# Generated deterministically by seda-macro-lef-normalizer-v1; recipe orfs-asap7-fakeram-m4-v1.
VERSION 5.8 ;
BUSBITCHARS "[]" ;
DIVIDERCHAR "/" ;

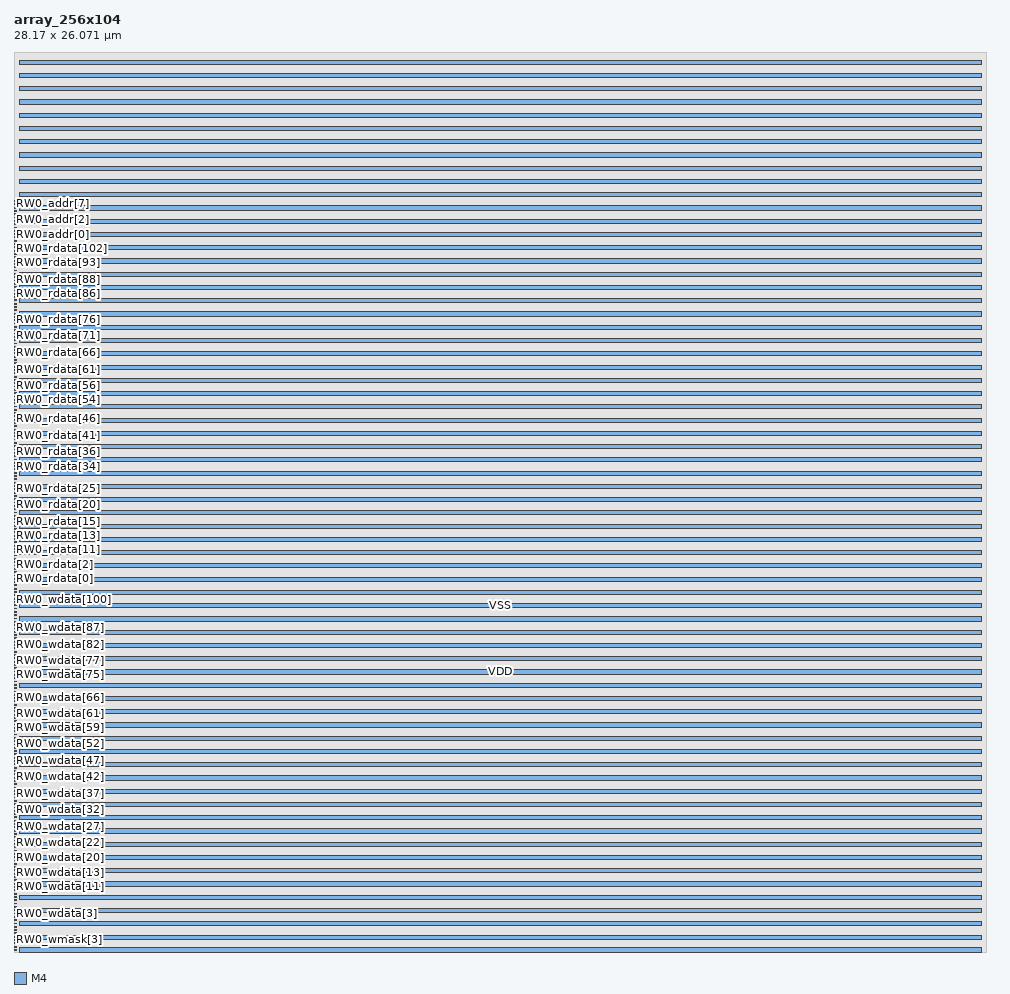
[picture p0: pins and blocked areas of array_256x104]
MACRO array_256x104
  FOREIGN array_256x104 0 0 ;
  CLASS BLOCK ;
  ORIGIN 0 0 ;
  SIZE 28.17 BY 26.071 ;
  SYMMETRY X Y R90 ;
  PIN RW0_wmask[0]
    DIRECTION INPUT ;
    USE SIGNAL ;
    SHAPE ABUTMENT ;
    PORT
      LAYER M4 ;
      RECT 0.000 0.048 0.084 0.072 ;
    END
  END RW0_wmask[0]
  PIN RW0_wmask[1]
    DIRECTION INPUT ;
    USE SIGNAL ;
    SHAPE ABUTMENT ;
    PORT
      LAYER M4 ;
      RECT 0.000 0.144 0.084 0.168 ;
    END
  END RW0_wmask[1]
  PIN RW0_wmask[2]
    DIRECTION INPUT ;
    USE SIGNAL ;
    SHAPE ABUTMENT ;
    PORT
      LAYER M4 ;
      RECT 0.000 0.240 0.084 0.264 ;
    END
  END RW0_wmask[2]
  PIN RW0_wmask[3]
    DIRECTION INPUT ;
    USE SIGNAL ;
    SHAPE ABUTMENT ;
    PORT
      LAYER M4 ;
      RECT 0.000 0.336 0.084 0.360 ;
    END
  END RW0_wmask[3]
  PIN RW0_wmask[4]
    DIRECTION INPUT ;
    USE SIGNAL ;
    SHAPE ABUTMENT ;
    PORT
      LAYER M4 ;
      RECT 0.000 0.432 0.084 0.456 ;
    END
  END RW0_wmask[4]
  PIN RW0_wmask[5]
    DIRECTION INPUT ;
    USE SIGNAL ;
    SHAPE ABUTMENT ;
    PORT
      LAYER M4 ;
      RECT 0.000 0.528 0.084 0.552 ;
    END
  END RW0_wmask[5]
  PIN RW0_wmask[6]
    DIRECTION INPUT ;
    USE SIGNAL ;
    SHAPE ABUTMENT ;
    PORT
      LAYER M4 ;
      RECT 0.000 0.624 0.084 0.648 ;
    END
  END RW0_wmask[6]
  PIN RW0_wmask[7]
    DIRECTION INPUT ;
    USE SIGNAL ;
    SHAPE ABUTMENT ;
    PORT
      LAYER M4 ;
      RECT 0.000 0.720 0.084 0.744 ;
    END
  END RW0_wmask[7]
  PIN RW0_wdata[0]
    DIRECTION INPUT ;
    USE SIGNAL ;
    SHAPE ABUTMENT ;
    PORT
      LAYER M4 ;
      RECT 0.000 0.816 0.084 0.840 ;
    END
  END RW0_wdata[0]
  PIN RW0_wdata[1]
    DIRECTION INPUT ;
    USE SIGNAL ;
    SHAPE ABUTMENT ;
    PORT
      LAYER M4 ;
      RECT 0.000 0.912 0.084 0.936 ;
    END
  END RW0_wdata[1]
  PIN RW0_wdata[2]
    DIRECTION INPUT ;
    USE SIGNAL ;
    SHAPE ABUTMENT ;
    PORT
      LAYER M4 ;
      RECT 0.000 1.008 0.084 1.032 ;
    END
  END RW0_wdata[2]
  PIN RW0_wdata[3]
    DIRECTION INPUT ;
    USE SIGNAL ;
    SHAPE ABUTMENT ;
    PORT
      LAYER M4 ;
      RECT 0.000 1.104 0.084 1.128 ;
    END
  END RW0_wdata[3]
  PIN RW0_wdata[4]
    DIRECTION INPUT ;
    USE SIGNAL ;
    SHAPE ABUTMENT ;
    PORT
      LAYER M4 ;
      RECT 0.000 1.200 0.084 1.224 ;
    END
  END RW0_wdata[4]
  PIN RW0_wdata[5]
    DIRECTION INPUT ;
    USE SIGNAL ;
    SHAPE ABUTMENT ;
    PORT
      LAYER M4 ;
      RECT 0.000 1.296 0.084 1.320 ;
    END
  END RW0_wdata[5]
  PIN RW0_wdata[6]
    DIRECTION INPUT ;
    USE SIGNAL ;
    SHAPE ABUTMENT ;
    PORT
      LAYER M4 ;
      RECT 0.000 1.392 0.084 1.416 ;
    END
  END RW0_wdata[6]
  PIN RW0_wdata[7]
    DIRECTION INPUT ;
    USE SIGNAL ;
    SHAPE ABUTMENT ;
    PORT
      LAYER M4 ;
      RECT 0.000 1.488 0.084 1.512 ;
    END
  END RW0_wdata[7]
  PIN RW0_wdata[8]
    DIRECTION INPUT ;
    USE SIGNAL ;
    SHAPE ABUTMENT ;
    PORT
      LAYER M4 ;
      RECT 0.000 1.584 0.084 1.608 ;
    END
  END RW0_wdata[8]
  PIN RW0_wdata[9]
    DIRECTION INPUT ;
    USE SIGNAL ;
    SHAPE ABUTMENT ;
    PORT
      LAYER M4 ;
      RECT 0.000 1.680 0.084 1.704 ;
    END
  END RW0_wdata[9]
  PIN RW0_wdata[10]
    DIRECTION INPUT ;
    USE SIGNAL ;
    SHAPE ABUTMENT ;
    PORT
      LAYER M4 ;
      RECT 0.000 1.776 0.084 1.800 ;
    END
  END RW0_wdata[10]
  PIN RW0_wdata[11]
    DIRECTION INPUT ;
    USE SIGNAL ;
    SHAPE ABUTMENT ;
    PORT
      LAYER M4 ;
      RECT 0.000 1.872 0.084 1.896 ;
    END
  END RW0_wdata[11]
  PIN RW0_wdata[12]
    DIRECTION INPUT ;
    USE SIGNAL ;
    SHAPE ABUTMENT ;
    PORT
      LAYER M4 ;
      RECT 0.000 1.968 0.084 1.992 ;
    END
  END RW0_wdata[12]
  PIN RW0_wdata[13]
    DIRECTION INPUT ;
    USE SIGNAL ;
    SHAPE ABUTMENT ;
    PORT
      LAYER M4 ;
      RECT 0.000 2.064 0.084 2.088 ;
    END
  END RW0_wdata[13]
  PIN RW0_wdata[14]
    DIRECTION INPUT ;
    USE SIGNAL ;
    SHAPE ABUTMENT ;
    PORT
      LAYER M4 ;
      RECT 0.000 2.160 0.084 2.184 ;
    END
  END RW0_wdata[14]
  PIN RW0_wdata[15]
    DIRECTION INPUT ;
    USE SIGNAL ;
    SHAPE ABUTMENT ;
    PORT
      LAYER M4 ;
      RECT 0.000 2.256 0.084 2.280 ;
    END
  END RW0_wdata[15]
  PIN RW0_wdata[16]
    DIRECTION INPUT ;
    USE SIGNAL ;
    SHAPE ABUTMENT ;
    PORT
      LAYER M4 ;
      RECT 0.000 2.352 0.084 2.376 ;
    END
  END RW0_wdata[16]
  PIN RW0_wdata[17]
    DIRECTION INPUT ;
    USE SIGNAL ;
    SHAPE ABUTMENT ;
    PORT
      LAYER M4 ;
      RECT 0.000 2.448 0.084 2.472 ;
    END
  END RW0_wdata[17]
  PIN RW0_wdata[18]
    DIRECTION INPUT ;
    USE SIGNAL ;
    SHAPE ABUTMENT ;
    PORT
      LAYER M4 ;
      RECT 0.000 2.544 0.084 2.568 ;
    END
  END RW0_wdata[18]
  PIN RW0_wdata[19]
    DIRECTION INPUT ;
    USE SIGNAL ;
    SHAPE ABUTMENT ;
    PORT
      LAYER M4 ;
      RECT 0.000 2.640 0.084 2.664 ;
    END
  END RW0_wdata[19]
  PIN RW0_wdata[20]
    DIRECTION INPUT ;
    USE SIGNAL ;
    SHAPE ABUTMENT ;
    PORT
      LAYER M4 ;
      RECT 0.000 2.736 0.084 2.760 ;
    END
  END RW0_wdata[20]
  PIN RW0_wdata[21]
    DIRECTION INPUT ;
    USE SIGNAL ;
    SHAPE ABUTMENT ;
    PORT
      LAYER M4 ;
      RECT 0.000 2.832 0.084 2.856 ;
    END
  END RW0_wdata[21]
  PIN RW0_wdata[22]
    DIRECTION INPUT ;
    USE SIGNAL ;
    SHAPE ABUTMENT ;
    PORT
      LAYER M4 ;
      RECT 0.000 2.928 0.084 2.952 ;
    END
  END RW0_wdata[22]
  PIN RW0_wdata[23]
    DIRECTION INPUT ;
    USE SIGNAL ;
    SHAPE ABUTMENT ;
    PORT
      LAYER M4 ;
      RECT 0.000 3.024 0.084 3.048 ;
    END
  END RW0_wdata[23]
  PIN RW0_wdata[24]
    DIRECTION INPUT ;
    USE SIGNAL ;
    SHAPE ABUTMENT ;
    PORT
      LAYER M4 ;
      RECT 0.000 3.120 0.084 3.144 ;
    END
  END RW0_wdata[24]
  PIN RW0_wdata[25]
    DIRECTION INPUT ;
    USE SIGNAL ;
    SHAPE ABUTMENT ;
    PORT
      LAYER M4 ;
      RECT 0.000 3.216 0.084 3.240 ;
    END
  END RW0_wdata[25]
  PIN RW0_wdata[26]
    DIRECTION INPUT ;
    USE SIGNAL ;
    SHAPE ABUTMENT ;
    PORT
      LAYER M4 ;
      RECT 0.000 3.312 0.084 3.336 ;
    END
  END RW0_wdata[26]
  PIN RW0_wdata[27]
    DIRECTION INPUT ;
    USE SIGNAL ;
    SHAPE ABUTMENT ;
    PORT
      LAYER M4 ;
      RECT 0.000 3.408 0.084 3.432 ;
    END
  END RW0_wdata[27]
  PIN RW0_wdata[28]
    DIRECTION INPUT ;
    USE SIGNAL ;
    SHAPE ABUTMENT ;
    PORT
      LAYER M4 ;
      RECT 0.000 3.504 0.084 3.528 ;
    END
  END RW0_wdata[28]
  PIN RW0_wdata[29]
    DIRECTION INPUT ;
    USE SIGNAL ;
    SHAPE ABUTMENT ;
    PORT
      LAYER M4 ;
      RECT 0.000 3.600 0.084 3.624 ;
    END
  END RW0_wdata[29]
  PIN RW0_wdata[30]
    DIRECTION INPUT ;
    USE SIGNAL ;
    SHAPE ABUTMENT ;
    PORT
      LAYER M4 ;
      RECT 0.000 3.696 0.084 3.720 ;
    END
  END RW0_wdata[30]
  PIN RW0_wdata[31]
    DIRECTION INPUT ;
    USE SIGNAL ;
    SHAPE ABUTMENT ;
    PORT
      LAYER M4 ;
      RECT 0.000 3.792 0.084 3.816 ;
    END
  END RW0_wdata[31]
  PIN RW0_wdata[32]
    DIRECTION INPUT ;
    USE SIGNAL ;
    SHAPE ABUTMENT ;
    PORT
      LAYER M4 ;
      RECT 0.000 3.888 0.084 3.912 ;
    END
  END RW0_wdata[32]
  PIN RW0_wdata[33]
    DIRECTION INPUT ;
    USE SIGNAL ;
    SHAPE ABUTMENT ;
    PORT
      LAYER M4 ;
      RECT 0.000 3.984 0.084 4.008 ;
    END
  END RW0_wdata[33]
  PIN RW0_wdata[34]
    DIRECTION INPUT ;
    USE SIGNAL ;
    SHAPE ABUTMENT ;
    PORT
      LAYER M4 ;
      RECT 0.000 4.080 0.084 4.104 ;
    END
  END RW0_wdata[34]
  PIN RW0_wdata[35]
    DIRECTION INPUT ;
    USE SIGNAL ;
    SHAPE ABUTMENT ;
    PORT
      LAYER M4 ;
      RECT 0.000 4.176 0.084 4.200 ;
    END
  END RW0_wdata[35]
  PIN RW0_wdata[36]
    DIRECTION INPUT ;
    USE SIGNAL ;
    SHAPE ABUTMENT ;
    PORT
      LAYER M4 ;
      RECT 0.000 4.272 0.084 4.296 ;
    END
  END RW0_wdata[36]
  PIN RW0_wdata[37]
    DIRECTION INPUT ;
    USE SIGNAL ;
    SHAPE ABUTMENT ;
    PORT
      LAYER M4 ;
      RECT 0.000 4.368 0.084 4.392 ;
    END
  END RW0_wdata[37]
  PIN RW0_wdata[38]
    DIRECTION INPUT ;
    USE SIGNAL ;
    SHAPE ABUTMENT ;
    PORT
      LAYER M4 ;
      RECT 0.000 4.464 0.084 4.488 ;
    END
  END RW0_wdata[38]
  PIN RW0_wdata[39]
    DIRECTION INPUT ;
    USE SIGNAL ;
    SHAPE ABUTMENT ;
    PORT
      LAYER M4 ;
      RECT 0.000 4.560 0.084 4.584 ;
    END
  END RW0_wdata[39]
  PIN RW0_wdata[40]
    DIRECTION INPUT ;
    USE SIGNAL ;
    SHAPE ABUTMENT ;
    PORT
      LAYER M4 ;
      RECT 0.000 4.656 0.084 4.680 ;
    END
  END RW0_wdata[40]
  PIN RW0_wdata[41]
    DIRECTION INPUT ;
    USE SIGNAL ;
    SHAPE ABUTMENT ;
    PORT
      LAYER M4 ;
      RECT 0.000 4.752 0.084 4.776 ;
    END
  END RW0_wdata[41]
  PIN RW0_wdata[42]
    DIRECTION INPUT ;
    USE SIGNAL ;
    SHAPE ABUTMENT ;
    PORT
      LAYER M4 ;
      RECT 0.000 4.848 0.084 4.872 ;
    END
  END RW0_wdata[42]
  PIN RW0_wdata[43]
    DIRECTION INPUT ;
    USE SIGNAL ;
    SHAPE ABUTMENT ;
    PORT
      LAYER M4 ;
      RECT 0.000 4.944 0.084 4.968 ;
    END
  END RW0_wdata[43]
  PIN RW0_wdata[44]
    DIRECTION INPUT ;
    USE SIGNAL ;
    SHAPE ABUTMENT ;
    PORT
      LAYER M4 ;
      RECT 0.000 5.040 0.084 5.064 ;
    END
  END RW0_wdata[44]
  PIN RW0_wdata[45]
    DIRECTION INPUT ;
    USE SIGNAL ;
    SHAPE ABUTMENT ;
    PORT
      LAYER M4 ;
      RECT 0.000 5.136 0.084 5.160 ;
    END
  END RW0_wdata[45]
  PIN RW0_wdata[46]
    DIRECTION INPUT ;
    USE SIGNAL ;
    SHAPE ABUTMENT ;
    PORT
      LAYER M4 ;
      RECT 0.000 5.232 0.084 5.256 ;
    END
  END RW0_wdata[46]
  PIN RW0_wdata[47]
    DIRECTION INPUT ;
    USE SIGNAL ;
    SHAPE ABUTMENT ;
    PORT
      LAYER M4 ;
      RECT 0.000 5.328 0.084 5.352 ;
    END
  END RW0_wdata[47]
  PIN RW0_wdata[48]
    DIRECTION INPUT ;
    USE SIGNAL ;
    SHAPE ABUTMENT ;
    PORT
      LAYER M4 ;
      RECT 0.000 5.424 0.084 5.448 ;
    END
  END RW0_wdata[48]
  PIN RW0_wdata[49]
    DIRECTION INPUT ;
    USE SIGNAL ;
    SHAPE ABUTMENT ;
    PORT
      LAYER M4 ;
      RECT 0.000 5.520 0.084 5.544 ;
    END
  END RW0_wdata[49]
  PIN RW0_wdata[50]
    DIRECTION INPUT ;
    USE SIGNAL ;
    SHAPE ABUTMENT ;
    PORT
      LAYER M4 ;
      RECT 0.000 5.616 0.084 5.640 ;
    END
  END RW0_wdata[50]
  PIN RW0_wdata[51]
    DIRECTION INPUT ;
    USE SIGNAL ;
    SHAPE ABUTMENT ;
    PORT
      LAYER M4 ;
      RECT 0.000 5.712 0.084 5.736 ;
    END
  END RW0_wdata[51]
  PIN RW0_wdata[52]
    DIRECTION INPUT ;
    USE SIGNAL ;
    SHAPE ABUTMENT ;
    PORT
      LAYER M4 ;
      RECT 0.000 5.808 0.084 5.832 ;
    END
  END RW0_wdata[52]
  PIN RW0_wdata[53]
    DIRECTION INPUT ;
    USE SIGNAL ;
    SHAPE ABUTMENT ;
    PORT
      LAYER M4 ;
      RECT 0.000 5.904 0.084 5.928 ;
    END
  END RW0_wdata[53]
  PIN RW0_wdata[54]
    DIRECTION INPUT ;
    USE SIGNAL ;
    SHAPE ABUTMENT ;
    PORT
      LAYER M4 ;
      RECT 0.000 6.000 0.084 6.024 ;
    END
  END RW0_wdata[54]
  PIN RW0_wdata[55]
    DIRECTION INPUT ;
    USE SIGNAL ;
    SHAPE ABUTMENT ;
    PORT
      LAYER M4 ;
      RECT 0.000 6.096 0.084 6.120 ;
    END
  END RW0_wdata[55]
  PIN RW0_wdata[56]
    DIRECTION INPUT ;
    USE SIGNAL ;
    SHAPE ABUTMENT ;
    PORT
      LAYER M4 ;
      RECT 0.000 6.192 0.084 6.216 ;
    END
  END RW0_wdata[56]
  PIN RW0_wdata[57]
    DIRECTION INPUT ;
    USE SIGNAL ;
    SHAPE ABUTMENT ;
    PORT
      LAYER M4 ;
      RECT 0.000 6.288 0.084 6.312 ;
    END
  END RW0_wdata[57]
  PIN RW0_wdata[58]
    DIRECTION INPUT ;
    USE SIGNAL ;
    SHAPE ABUTMENT ;
    PORT
      LAYER M4 ;
      RECT 0.000 6.384 0.084 6.408 ;
    END
  END RW0_wdata[58]
  PIN RW0_wdata[59]
    DIRECTION INPUT ;
    USE SIGNAL ;
    SHAPE ABUTMENT ;
    PORT
      LAYER M4 ;
      RECT 0.000 6.480 0.084 6.504 ;
    END
  END RW0_wdata[59]
  PIN RW0_wdata[60]
    DIRECTION INPUT ;
    USE SIGNAL ;
    SHAPE ABUTMENT ;
    PORT
      LAYER M4 ;
      RECT 0.000 6.576 0.084 6.600 ;
    END
  END RW0_wdata[60]
  PIN RW0_wdata[61]
    DIRECTION INPUT ;
    USE SIGNAL ;
    SHAPE ABUTMENT ;
    PORT
      LAYER M4 ;
      RECT 0.000 6.672 0.084 6.696 ;
    END
  END RW0_wdata[61]
  PIN RW0_wdata[62]
    DIRECTION INPUT ;
    USE SIGNAL ;
    SHAPE ABUTMENT ;
    PORT
      LAYER M4 ;
      RECT 0.000 6.768 0.084 6.792 ;
    END
  END RW0_wdata[62]
  PIN RW0_wdata[63]
    DIRECTION INPUT ;
    USE SIGNAL ;
    SHAPE ABUTMENT ;
    PORT
      LAYER M4 ;
      RECT 0.000 6.864 0.084 6.888 ;
    END
  END RW0_wdata[63]
  PIN RW0_wdata[64]
    DIRECTION INPUT ;
    USE SIGNAL ;
    SHAPE ABUTMENT ;
    PORT
      LAYER M4 ;
      RECT 0.000 6.960 0.084 6.984 ;
    END
  END RW0_wdata[64]
  PIN RW0_wdata[65]
    DIRECTION INPUT ;
    USE SIGNAL ;
    SHAPE ABUTMENT ;
    PORT
      LAYER M4 ;
      RECT 0.000 7.056 0.084 7.080 ;
    END
  END RW0_wdata[65]
  PIN RW0_wdata[66]
    DIRECTION INPUT ;
    USE SIGNAL ;
    SHAPE ABUTMENT ;
    PORT
      LAYER M4 ;
      RECT 0.000 7.152 0.084 7.176 ;
    END
  END RW0_wdata[66]
  PIN RW0_wdata[67]
    DIRECTION INPUT ;
    USE SIGNAL ;
    SHAPE ABUTMENT ;
    PORT
      LAYER M4 ;
      RECT 0.000 7.248 0.084 7.272 ;
    END
  END RW0_wdata[67]
  PIN RW0_wdata[68]
    DIRECTION INPUT ;
    USE SIGNAL ;
    SHAPE ABUTMENT ;
    PORT
      LAYER M4 ;
      RECT 0.000 7.344 0.084 7.368 ;
    END
  END RW0_wdata[68]
  PIN RW0_wdata[69]
    DIRECTION INPUT ;
    USE SIGNAL ;
    SHAPE ABUTMENT ;
    PORT
      LAYER M4 ;
      RECT 0.000 7.440 0.084 7.464 ;
    END
  END RW0_wdata[69]
  PIN RW0_wdata[70]
    DIRECTION INPUT ;
    USE SIGNAL ;
    SHAPE ABUTMENT ;
    PORT
      LAYER M4 ;
      RECT 0.000 7.536 0.084 7.560 ;
    END
  END RW0_wdata[70]
  PIN RW0_wdata[71]
    DIRECTION INPUT ;
    USE SIGNAL ;
    SHAPE ABUTMENT ;
    PORT
      LAYER M4 ;
      RECT 0.000 7.632 0.084 7.656 ;
    END
  END RW0_wdata[71]
  PIN RW0_wdata[72]
    DIRECTION INPUT ;
    USE SIGNAL ;
    SHAPE ABUTMENT ;
    PORT
      LAYER M4 ;
      RECT 0.000 7.728 0.084 7.752 ;
    END
  END RW0_wdata[72]
  PIN RW0_wdata[73]
    DIRECTION INPUT ;
    USE SIGNAL ;
    SHAPE ABUTMENT ;
    PORT
      LAYER M4 ;
      RECT 0.000 7.824 0.084 7.848 ;
    END
  END RW0_wdata[73]
  PIN RW0_wdata[74]
    DIRECTION INPUT ;
    USE SIGNAL ;
    SHAPE ABUTMENT ;
    PORT
      LAYER M4 ;
      RECT 0.000 7.920 0.084 7.944 ;
    END
  END RW0_wdata[74]
  PIN RW0_wdata[75]
    DIRECTION INPUT ;
    USE SIGNAL ;
    SHAPE ABUTMENT ;
    PORT
      LAYER M4 ;
      RECT 0.000 8.016 0.084 8.040 ;
    END
  END RW0_wdata[75]
  PIN RW0_wdata[76]
    DIRECTION INPUT ;
    USE SIGNAL ;
    SHAPE ABUTMENT ;
    PORT
      LAYER M4 ;
      RECT 0.000 8.112 0.084 8.136 ;
    END
  END RW0_wdata[76]
  PIN RW0_wdata[77]
    DIRECTION INPUT ;
    USE SIGNAL ;
    SHAPE ABUTMENT ;
    PORT
      LAYER M4 ;
      RECT 0.000 8.208 0.084 8.232 ;
    END
  END RW0_wdata[77]
  PIN RW0_wdata[78]
    DIRECTION INPUT ;
    USE SIGNAL ;
    SHAPE ABUTMENT ;
    PORT
      LAYER M4 ;
      RECT 0.000 8.304 0.084 8.328 ;
    END
  END RW0_wdata[78]
  PIN RW0_wdata[79]
    DIRECTION INPUT ;
    USE SIGNAL ;
    SHAPE ABUTMENT ;
    PORT
      LAYER M4 ;
      RECT 0.000 8.400 0.084 8.424 ;
    END
  END RW0_wdata[79]
  PIN RW0_wdata[80]
    DIRECTION INPUT ;
    USE SIGNAL ;
    SHAPE ABUTMENT ;
    PORT
      LAYER M4 ;
      RECT 0.000 8.496 0.084 8.520 ;
    END
  END RW0_wdata[80]
  PIN RW0_wdata[81]
    DIRECTION INPUT ;
    USE SIGNAL ;
    SHAPE ABUTMENT ;
    PORT
      LAYER M4 ;
      RECT 0.000 8.592 0.084 8.616 ;
    END
  END RW0_wdata[81]
  PIN RW0_wdata[82]
    DIRECTION INPUT ;
    USE SIGNAL ;
    SHAPE ABUTMENT ;
    PORT
      LAYER M4 ;
      RECT 0.000 8.688 0.084 8.712 ;
    END
  END RW0_wdata[82]
  PIN RW0_wdata[83]
    DIRECTION INPUT ;
    USE SIGNAL ;
    SHAPE ABUTMENT ;
    PORT
      LAYER M4 ;
      RECT 0.000 8.784 0.084 8.808 ;
    END
  END RW0_wdata[83]
  PIN RW0_wdata[84]
    DIRECTION INPUT ;
    USE SIGNAL ;
    SHAPE ABUTMENT ;
    PORT
      LAYER M4 ;
      RECT 0.000 8.880 0.084 8.904 ;
    END
  END RW0_wdata[84]
  PIN RW0_wdata[85]
    DIRECTION INPUT ;
    USE SIGNAL ;
    SHAPE ABUTMENT ;
    PORT
      LAYER M4 ;
      RECT 0.000 8.976 0.084 9.000 ;
    END
  END RW0_wdata[85]
  PIN RW0_wdata[86]
    DIRECTION INPUT ;
    USE SIGNAL ;
    SHAPE ABUTMENT ;
    PORT
      LAYER M4 ;
      RECT 0.000 9.072 0.084 9.096 ;
    END
  END RW0_wdata[86]
  PIN RW0_wdata[87]
    DIRECTION INPUT ;
    USE SIGNAL ;
    SHAPE ABUTMENT ;
    PORT
      LAYER M4 ;
      RECT 0.000 9.168 0.084 9.192 ;
    END
  END RW0_wdata[87]
  PIN RW0_wdata[88]
    DIRECTION INPUT ;
    USE SIGNAL ;
    SHAPE ABUTMENT ;
    PORT
      LAYER M4 ;
      RECT 0.000 9.264 0.084 9.288 ;
    END
  END RW0_wdata[88]
  PIN RW0_wdata[89]
    DIRECTION INPUT ;
    USE SIGNAL ;
    SHAPE ABUTMENT ;
    PORT
      LAYER M4 ;
      RECT 0.000 9.360 0.084 9.384 ;
    END
  END RW0_wdata[89]
  PIN RW0_wdata[90]
    DIRECTION INPUT ;
    USE SIGNAL ;
    SHAPE ABUTMENT ;
    PORT
      LAYER M4 ;
      RECT 0.000 9.456 0.084 9.480 ;
    END
  END RW0_wdata[90]
  PIN RW0_wdata[91]
    DIRECTION INPUT ;
    USE SIGNAL ;
    SHAPE ABUTMENT ;
    PORT
      LAYER M4 ;
      RECT 0.000 9.552 0.084 9.576 ;
    END
  END RW0_wdata[91]
  PIN RW0_wdata[92]
    DIRECTION INPUT ;
    USE SIGNAL ;
    SHAPE ABUTMENT ;
    PORT
      LAYER M4 ;
      RECT 0.000 9.648 0.084 9.672 ;
    END
  END RW0_wdata[92]
  PIN RW0_wdata[93]
    DIRECTION INPUT ;
    USE SIGNAL ;
    SHAPE ABUTMENT ;
    PORT
      LAYER M4 ;
      RECT 0.000 9.744 0.084 9.768 ;
    END
  END RW0_wdata[93]
  PIN RW0_wdata[94]
    DIRECTION INPUT ;
    USE SIGNAL ;
    SHAPE ABUTMENT ;
    PORT
      LAYER M4 ;
      RECT 0.000 9.840 0.084 9.864 ;
    END
  END RW0_wdata[94]
  PIN RW0_wdata[95]
    DIRECTION INPUT ;
    USE SIGNAL ;
    SHAPE ABUTMENT ;
    PORT
      LAYER M4 ;
      RECT 0.000 9.936 0.084 9.960 ;
    END
  END RW0_wdata[95]
  PIN RW0_wdata[96]
    DIRECTION INPUT ;
    USE SIGNAL ;
    SHAPE ABUTMENT ;
    PORT
      LAYER M4 ;
      RECT 0.000 10.032 0.084 10.056 ;
    END
  END RW0_wdata[96]
  PIN RW0_wdata[97]
    DIRECTION INPUT ;
    USE SIGNAL ;
    SHAPE ABUTMENT ;
    PORT
      LAYER M4 ;
      RECT 0.000 10.128 0.084 10.152 ;
    END
  END RW0_wdata[97]
  PIN RW0_wdata[98]
    DIRECTION INPUT ;
    USE SIGNAL ;
    SHAPE ABUTMENT ;
    PORT
      LAYER M4 ;
      RECT 0.000 10.224 0.084 10.248 ;
    END
  END RW0_wdata[98]
  PIN RW0_wdata[99]
    DIRECTION INPUT ;
    USE SIGNAL ;
    SHAPE ABUTMENT ;
    PORT
      LAYER M4 ;
      RECT 0.000 10.320 0.084 10.344 ;
    END
  END RW0_wdata[99]
  PIN RW0_wdata[100]
    DIRECTION INPUT ;
    USE SIGNAL ;
    SHAPE ABUTMENT ;
    PORT
      LAYER M4 ;
      RECT 0.000 10.416 0.084 10.440 ;
    END
  END RW0_wdata[100]
  PIN RW0_wdata[101]
    DIRECTION INPUT ;
    USE SIGNAL ;
    SHAPE ABUTMENT ;
    PORT
      LAYER M4 ;
      RECT 0.000 10.512 0.084 10.536 ;
    END
  END RW0_wdata[101]
  PIN RW0_wdata[102]
    DIRECTION INPUT ;
    USE SIGNAL ;
    SHAPE ABUTMENT ;
    PORT
      LAYER M4 ;
      RECT 0.000 10.608 0.084 10.632 ;
    END
  END RW0_wdata[102]
  PIN RW0_wdata[103]
    DIRECTION INPUT ;
    USE SIGNAL ;
    SHAPE ABUTMENT ;
    PORT
      LAYER M4 ;
      RECT 0.000 10.704 0.084 10.728 ;
    END
  END RW0_wdata[103]
  PIN RW0_rdata[0]
    DIRECTION OUTPUT ;
    USE SIGNAL ;
    SHAPE ABUTMENT ;
    PORT
      LAYER M4 ;
      RECT 0.000 10.800 0.084 10.824 ;
    END
  END RW0_rdata[0]
  PIN RW0_rdata[1]
    DIRECTION OUTPUT ;
    USE SIGNAL ;
    SHAPE ABUTMENT ;
    PORT
      LAYER M4 ;
      RECT 0.000 10.896 0.084 10.920 ;
    END
  END RW0_rdata[1]
  PIN RW0_rdata[2]
    DIRECTION OUTPUT ;
    USE SIGNAL ;
    SHAPE ABUTMENT ;
    PORT
      LAYER M4 ;
      RECT 0.000 10.992 0.084 11.016 ;
    END
  END RW0_rdata[2]
  PIN RW0_rdata[3]
    DIRECTION OUTPUT ;
    USE SIGNAL ;
    SHAPE ABUTMENT ;
    PORT
      LAYER M4 ;
      RECT 0.000 11.088 0.084 11.112 ;
    END
  END RW0_rdata[3]
  PIN RW0_rdata[4]
    DIRECTION OUTPUT ;
    USE SIGNAL ;
    SHAPE ABUTMENT ;
    PORT
      LAYER M4 ;
      RECT 0.000 11.184 0.084 11.208 ;
    END
  END RW0_rdata[4]
  PIN RW0_rdata[5]
    DIRECTION OUTPUT ;
    USE SIGNAL ;
    SHAPE ABUTMENT ;
    PORT
      LAYER M4 ;
      RECT 0.000 11.280 0.084 11.304 ;
    END
  END RW0_rdata[5]
  PIN RW0_rdata[6]
    DIRECTION OUTPUT ;
    USE SIGNAL ;
    SHAPE ABUTMENT ;
    PORT
      LAYER M4 ;
      RECT 0.000 11.376 0.084 11.400 ;
    END
  END RW0_rdata[6]
  PIN RW0_rdata[7]
    DIRECTION OUTPUT ;
    USE SIGNAL ;
    SHAPE ABUTMENT ;
    PORT
      LAYER M4 ;
      RECT 0.000 11.472 0.084 11.496 ;
    END
  END RW0_rdata[7]
  PIN RW0_rdata[8]
    DIRECTION OUTPUT ;
    USE SIGNAL ;
    SHAPE ABUTMENT ;
    PORT
      LAYER M4 ;
      RECT 0.000 11.568 0.084 11.592 ;
    END
  END RW0_rdata[8]
  PIN RW0_rdata[9]
    DIRECTION OUTPUT ;
    USE SIGNAL ;
    SHAPE ABUTMENT ;
    PORT
      LAYER M4 ;
      RECT 0.000 11.664 0.084 11.688 ;
    END
  END RW0_rdata[9]
  PIN RW0_rdata[10]
    DIRECTION OUTPUT ;
    USE SIGNAL ;
    SHAPE ABUTMENT ;
    PORT
      LAYER M4 ;
      RECT 0.000 11.760 0.084 11.784 ;
    END
  END RW0_rdata[10]
  PIN RW0_rdata[11]
    DIRECTION OUTPUT ;
    USE SIGNAL ;
    SHAPE ABUTMENT ;
    PORT
      LAYER M4 ;
      RECT 0.000 11.856 0.084 11.880 ;
    END
  END RW0_rdata[11]
  PIN RW0_rdata[12]
    DIRECTION OUTPUT ;
    USE SIGNAL ;
    SHAPE ABUTMENT ;
    PORT
      LAYER M4 ;
      RECT 0.000 11.952 0.084 11.976 ;
    END
  END RW0_rdata[12]
  PIN RW0_rdata[13]
    DIRECTION OUTPUT ;
    USE SIGNAL ;
    SHAPE ABUTMENT ;
    PORT
      LAYER M4 ;
      RECT 0.000 12.048 0.084 12.072 ;
    END
  END RW0_rdata[13]
  PIN RW0_rdata[14]
    DIRECTION OUTPUT ;
    USE SIGNAL ;
    SHAPE ABUTMENT ;
    PORT
      LAYER M4 ;
      RECT 0.000 12.144 0.084 12.168 ;
    END
  END RW0_rdata[14]
  PIN RW0_rdata[15]
    DIRECTION OUTPUT ;
    USE SIGNAL ;
    SHAPE ABUTMENT ;
    PORT
      LAYER M4 ;
      RECT 0.000 12.240 0.084 12.264 ;
    END
  END RW0_rdata[15]
  PIN RW0_rdata[16]
    DIRECTION OUTPUT ;
    USE SIGNAL ;
    SHAPE ABUTMENT ;
    PORT
      LAYER M4 ;
      RECT 0.000 12.336 0.084 12.360 ;
    END
  END RW0_rdata[16]
  PIN RW0_rdata[17]
    DIRECTION OUTPUT ;
    USE SIGNAL ;
    SHAPE ABUTMENT ;
    PORT
      LAYER M4 ;
      RECT 0.000 12.432 0.084 12.456 ;
    END
  END RW0_rdata[17]
  PIN RW0_rdata[18]
    DIRECTION OUTPUT ;
    USE SIGNAL ;
    SHAPE ABUTMENT ;
    PORT
      LAYER M4 ;
      RECT 0.000 12.528 0.084 12.552 ;
    END
  END RW0_rdata[18]
  PIN RW0_rdata[19]
    DIRECTION OUTPUT ;
    USE SIGNAL ;
    SHAPE ABUTMENT ;
    PORT
      LAYER M4 ;
      RECT 0.000 12.624 0.084 12.648 ;
    END
  END RW0_rdata[19]
  PIN RW0_rdata[20]
    DIRECTION OUTPUT ;
    USE SIGNAL ;
    SHAPE ABUTMENT ;
    PORT
      LAYER M4 ;
      RECT 0.000 12.720 0.084 12.744 ;
    END
  END RW0_rdata[20]
  PIN RW0_rdata[21]
    DIRECTION OUTPUT ;
    USE SIGNAL ;
    SHAPE ABUTMENT ;
    PORT
      LAYER M4 ;
      RECT 0.000 12.816 0.084 12.840 ;
    END
  END RW0_rdata[21]
  PIN RW0_rdata[22]
    DIRECTION OUTPUT ;
    USE SIGNAL ;
    SHAPE ABUTMENT ;
    PORT
      LAYER M4 ;
      RECT 0.000 12.912 0.084 12.936 ;
    END
  END RW0_rdata[22]
  PIN RW0_rdata[23]
    DIRECTION OUTPUT ;
    USE SIGNAL ;
    SHAPE ABUTMENT ;
    PORT
      LAYER M4 ;
      RECT 0.000 13.008 0.084 13.032 ;
    END
  END RW0_rdata[23]
  PIN RW0_rdata[24]
    DIRECTION OUTPUT ;
    USE SIGNAL ;
    SHAPE ABUTMENT ;
    PORT
      LAYER M4 ;
      RECT 0.000 13.104 0.084 13.128 ;
    END
  END RW0_rdata[24]
  PIN RW0_rdata[25]
    DIRECTION OUTPUT ;
    USE SIGNAL ;
    SHAPE ABUTMENT ;
    PORT
      LAYER M4 ;
      RECT 0.000 13.200 0.084 13.224 ;
    END
  END RW0_rdata[25]
  PIN RW0_rdata[26]
    DIRECTION OUTPUT ;
    USE SIGNAL ;
    SHAPE ABUTMENT ;
    PORT
      LAYER M4 ;
      RECT 0.000 13.296 0.084 13.320 ;
    END
  END RW0_rdata[26]
  PIN RW0_rdata[27]
    DIRECTION OUTPUT ;
    USE SIGNAL ;
    SHAPE ABUTMENT ;
    PORT
      LAYER M4 ;
      RECT 0.000 13.392 0.084 13.416 ;
    END
  END RW0_rdata[27]
  PIN RW0_rdata[28]
    DIRECTION OUTPUT ;
    USE SIGNAL ;
    SHAPE ABUTMENT ;
    PORT
      LAYER M4 ;
      RECT 0.000 13.488 0.084 13.512 ;
    END
  END RW0_rdata[28]
  PIN RW0_rdata[29]
    DIRECTION OUTPUT ;
    USE SIGNAL ;
    SHAPE ABUTMENT ;
    PORT
      LAYER M4 ;
      RECT 0.000 13.584 0.084 13.608 ;
    END
  END RW0_rdata[29]
  PIN RW0_rdata[30]
    DIRECTION OUTPUT ;
    USE SIGNAL ;
    SHAPE ABUTMENT ;
    PORT
      LAYER M4 ;
      RECT 0.000 13.680 0.084 13.704 ;
    END
  END RW0_rdata[30]
  PIN RW0_rdata[31]
    DIRECTION OUTPUT ;
    USE SIGNAL ;
    SHAPE ABUTMENT ;
    PORT
      LAYER M4 ;
      RECT 0.000 13.776 0.084 13.800 ;
    END
  END RW0_rdata[31]
  PIN RW0_rdata[32]
    DIRECTION OUTPUT ;
    USE SIGNAL ;
    SHAPE ABUTMENT ;
    PORT
      LAYER M4 ;
      RECT 0.000 13.872 0.084 13.896 ;
    END
  END RW0_rdata[32]
  PIN RW0_rdata[33]
    DIRECTION OUTPUT ;
    USE SIGNAL ;
    SHAPE ABUTMENT ;
    PORT
      LAYER M4 ;
      RECT 0.000 13.968 0.084 13.992 ;
    END
  END RW0_rdata[33]
  PIN RW0_rdata[34]
    DIRECTION OUTPUT ;
    USE SIGNAL ;
    SHAPE ABUTMENT ;
    PORT
      LAYER M4 ;
      RECT 0.000 14.064 0.084 14.088 ;
    END
  END RW0_rdata[34]
  PIN RW0_rdata[35]
    DIRECTION OUTPUT ;
    USE SIGNAL ;
    SHAPE ABUTMENT ;
    PORT
      LAYER M4 ;
      RECT 0.000 14.160 0.084 14.184 ;
    END
  END RW0_rdata[35]
  PIN RW0_rdata[36]
    DIRECTION OUTPUT ;
    USE SIGNAL ;
    SHAPE ABUTMENT ;
    PORT
      LAYER M4 ;
      RECT 0.000 14.256 0.084 14.280 ;
    END
  END RW0_rdata[36]
  PIN RW0_rdata[37]
    DIRECTION OUTPUT ;
    USE SIGNAL ;
    SHAPE ABUTMENT ;
    PORT
      LAYER M4 ;
      RECT 0.000 14.352 0.084 14.376 ;
    END
  END RW0_rdata[37]
  PIN RW0_rdata[38]
    DIRECTION OUTPUT ;
    USE SIGNAL ;
    SHAPE ABUTMENT ;
    PORT
      LAYER M4 ;
      RECT 0.000 14.448 0.084 14.472 ;
    END
  END RW0_rdata[38]
  PIN RW0_rdata[39]
    DIRECTION OUTPUT ;
    USE SIGNAL ;
    SHAPE ABUTMENT ;
    PORT
      LAYER M4 ;
      RECT 0.000 14.544 0.084 14.568 ;
    END
  END RW0_rdata[39]
  PIN RW0_rdata[40]
    DIRECTION OUTPUT ;
    USE SIGNAL ;
    SHAPE ABUTMENT ;
    PORT
      LAYER M4 ;
      RECT 0.000 14.640 0.084 14.664 ;
    END
  END RW0_rdata[40]
  PIN RW0_rdata[41]
    DIRECTION OUTPUT ;
    USE SIGNAL ;
    SHAPE ABUTMENT ;
    PORT
      LAYER M4 ;
      RECT 0.000 14.736 0.084 14.760 ;
    END
  END RW0_rdata[41]
  PIN RW0_rdata[42]
    DIRECTION OUTPUT ;
    USE SIGNAL ;
    SHAPE ABUTMENT ;
    PORT
      LAYER M4 ;
      RECT 0.000 14.832 0.084 14.856 ;
    END
  END RW0_rdata[42]
  PIN RW0_rdata[43]
    DIRECTION OUTPUT ;
    USE SIGNAL ;
    SHAPE ABUTMENT ;
    PORT
      LAYER M4 ;
      RECT 0.000 14.928 0.084 14.952 ;
    END
  END RW0_rdata[43]
  PIN RW0_rdata[44]
    DIRECTION OUTPUT ;
    USE SIGNAL ;
    SHAPE ABUTMENT ;
    PORT
      LAYER M4 ;
      RECT 0.000 15.024 0.084 15.048 ;
    END
  END RW0_rdata[44]
  PIN RW0_rdata[45]
    DIRECTION OUTPUT ;
    USE SIGNAL ;
    SHAPE ABUTMENT ;
    PORT
      LAYER M4 ;
      RECT 0.000 15.120 0.084 15.144 ;
    END
  END RW0_rdata[45]
  PIN RW0_rdata[46]
    DIRECTION OUTPUT ;
    USE SIGNAL ;
    SHAPE ABUTMENT ;
    PORT
      LAYER M4 ;
      RECT 0.000 15.216 0.084 15.240 ;
    END
  END RW0_rdata[46]
  PIN RW0_rdata[47]
    DIRECTION OUTPUT ;
    USE SIGNAL ;
    SHAPE ABUTMENT ;
    PORT
      LAYER M4 ;
      RECT 0.000 15.312 0.084 15.336 ;
    END
  END RW0_rdata[47]
  PIN RW0_rdata[48]
    DIRECTION OUTPUT ;
    USE SIGNAL ;
    SHAPE ABUTMENT ;
    PORT
      LAYER M4 ;
      RECT 0.000 15.408 0.084 15.432 ;
    END
  END RW0_rdata[48]
  PIN RW0_rdata[49]
    DIRECTION OUTPUT ;
    USE SIGNAL ;
    SHAPE ABUTMENT ;
    PORT
      LAYER M4 ;
      RECT 0.000 15.504 0.084 15.528 ;
    END
  END RW0_rdata[49]
  PIN RW0_rdata[50]
    DIRECTION OUTPUT ;
    USE SIGNAL ;
    SHAPE ABUTMENT ;
    PORT
      LAYER M4 ;
      RECT 0.000 15.600 0.084 15.624 ;
    END
  END RW0_rdata[50]
  PIN RW0_rdata[51]
    DIRECTION OUTPUT ;
    USE SIGNAL ;
    SHAPE ABUTMENT ;
    PORT
      LAYER M4 ;
      RECT 0.000 15.696 0.084 15.720 ;
    END
  END RW0_rdata[51]
  PIN RW0_rdata[52]
    DIRECTION OUTPUT ;
    USE SIGNAL ;
    SHAPE ABUTMENT ;
    PORT
      LAYER M4 ;
      RECT 0.000 15.792 0.084 15.816 ;
    END
  END RW0_rdata[52]
  PIN RW0_rdata[53]
    DIRECTION OUTPUT ;
    USE SIGNAL ;
    SHAPE ABUTMENT ;
    PORT
      LAYER M4 ;
      RECT 0.000 15.888 0.084 15.912 ;
    END
  END RW0_rdata[53]
  PIN RW0_rdata[54]
    DIRECTION OUTPUT ;
    USE SIGNAL ;
    SHAPE ABUTMENT ;
    PORT
      LAYER M4 ;
      RECT 0.000 15.984 0.084 16.008 ;
    END
  END RW0_rdata[54]
  PIN RW0_rdata[55]
    DIRECTION OUTPUT ;
    USE SIGNAL ;
    SHAPE ABUTMENT ;
    PORT
      LAYER M4 ;
      RECT 0.000 16.080 0.084 16.104 ;
    END
  END RW0_rdata[55]
  PIN RW0_rdata[56]
    DIRECTION OUTPUT ;
    USE SIGNAL ;
    SHAPE ABUTMENT ;
    PORT
      LAYER M4 ;
      RECT 0.000 16.176 0.084 16.200 ;
    END
  END RW0_rdata[56]
  PIN RW0_rdata[57]
    DIRECTION OUTPUT ;
    USE SIGNAL ;
    SHAPE ABUTMENT ;
    PORT
      LAYER M4 ;
      RECT 0.000 16.272 0.084 16.296 ;
    END
  END RW0_rdata[57]
  PIN RW0_rdata[58]
    DIRECTION OUTPUT ;
    USE SIGNAL ;
    SHAPE ABUTMENT ;
    PORT
      LAYER M4 ;
      RECT 0.000 16.368 0.084 16.392 ;
    END
  END RW0_rdata[58]
  PIN RW0_rdata[59]
    DIRECTION OUTPUT ;
    USE SIGNAL ;
    SHAPE ABUTMENT ;
    PORT
      LAYER M4 ;
      RECT 0.000 16.464 0.084 16.488 ;
    END
  END RW0_rdata[59]
  PIN RW0_rdata[60]
    DIRECTION OUTPUT ;
    USE SIGNAL ;
    SHAPE ABUTMENT ;
    PORT
      LAYER M4 ;
      RECT 0.000 16.560 0.084 16.584 ;
    END
  END RW0_rdata[60]
  PIN RW0_rdata[61]
    DIRECTION OUTPUT ;
    USE SIGNAL ;
    SHAPE ABUTMENT ;
    PORT
      LAYER M4 ;
      RECT 0.000 16.656 0.084 16.680 ;
    END
  END RW0_rdata[61]
  PIN RW0_rdata[62]
    DIRECTION OUTPUT ;
    USE SIGNAL ;
    SHAPE ABUTMENT ;
    PORT
      LAYER M4 ;
      RECT 0.000 16.752 0.084 16.776 ;
    END
  END RW0_rdata[62]
  PIN RW0_rdata[63]
    DIRECTION OUTPUT ;
    USE SIGNAL ;
    SHAPE ABUTMENT ;
    PORT
      LAYER M4 ;
      RECT 0.000 16.848 0.084 16.872 ;
    END
  END RW0_rdata[63]
  PIN RW0_rdata[64]
    DIRECTION OUTPUT ;
    USE SIGNAL ;
    SHAPE ABUTMENT ;
    PORT
      LAYER M4 ;
      RECT 0.000 16.944 0.084 16.968 ;
    END
  END RW0_rdata[64]
  PIN RW0_rdata[65]
    DIRECTION OUTPUT ;
    USE SIGNAL ;
    SHAPE ABUTMENT ;
    PORT
      LAYER M4 ;
      RECT 0.000 17.040 0.084 17.064 ;
    END
  END RW0_rdata[65]
  PIN RW0_rdata[66]
    DIRECTION OUTPUT ;
    USE SIGNAL ;
    SHAPE ABUTMENT ;
    PORT
      LAYER M4 ;
      RECT 0.000 17.136 0.084 17.160 ;
    END
  END RW0_rdata[66]
  PIN RW0_rdata[67]
    DIRECTION OUTPUT ;
    USE SIGNAL ;
    SHAPE ABUTMENT ;
    PORT
      LAYER M4 ;
      RECT 0.000 17.232 0.084 17.256 ;
    END
  END RW0_rdata[67]
  PIN RW0_rdata[68]
    DIRECTION OUTPUT ;
    USE SIGNAL ;
    SHAPE ABUTMENT ;
    PORT
      LAYER M4 ;
      RECT 0.000 17.328 0.084 17.352 ;
    END
  END RW0_rdata[68]
  PIN RW0_rdata[69]
    DIRECTION OUTPUT ;
    USE SIGNAL ;
    SHAPE ABUTMENT ;
    PORT
      LAYER M4 ;
      RECT 0.000 17.424 0.084 17.448 ;
    END
  END RW0_rdata[69]
  PIN RW0_rdata[70]
    DIRECTION OUTPUT ;
    USE SIGNAL ;
    SHAPE ABUTMENT ;
    PORT
      LAYER M4 ;
      RECT 0.000 17.520 0.084 17.544 ;
    END
  END RW0_rdata[70]
  PIN RW0_rdata[71]
    DIRECTION OUTPUT ;
    USE SIGNAL ;
    SHAPE ABUTMENT ;
    PORT
      LAYER M4 ;
      RECT 0.000 17.616 0.084 17.640 ;
    END
  END RW0_rdata[71]
  PIN RW0_rdata[72]
    DIRECTION OUTPUT ;
    USE SIGNAL ;
    SHAPE ABUTMENT ;
    PORT
      LAYER M4 ;
      RECT 0.000 17.712 0.084 17.736 ;
    END
  END RW0_rdata[72]
  PIN RW0_rdata[73]
    DIRECTION OUTPUT ;
    USE SIGNAL ;
    SHAPE ABUTMENT ;
    PORT
      LAYER M4 ;
      RECT 0.000 17.808 0.084 17.832 ;
    END
  END RW0_rdata[73]
  PIN RW0_rdata[74]
    DIRECTION OUTPUT ;
    USE SIGNAL ;
    SHAPE ABUTMENT ;
    PORT
      LAYER M4 ;
      RECT 0.000 17.904 0.084 17.928 ;
    END
  END RW0_rdata[74]
  PIN RW0_rdata[75]
    DIRECTION OUTPUT ;
    USE SIGNAL ;
    SHAPE ABUTMENT ;
    PORT
      LAYER M4 ;
      RECT 0.000 18.000 0.084 18.024 ;
    END
  END RW0_rdata[75]
  PIN RW0_rdata[76]
    DIRECTION OUTPUT ;
    USE SIGNAL ;
    SHAPE ABUTMENT ;
    PORT
      LAYER M4 ;
      RECT 0.000 18.096 0.084 18.120 ;
    END
  END RW0_rdata[76]
  PIN RW0_rdata[77]
    DIRECTION OUTPUT ;
    USE SIGNAL ;
    SHAPE ABUTMENT ;
    PORT
      LAYER M4 ;
      RECT 0.000 18.192 0.084 18.216 ;
    END
  END RW0_rdata[77]
  PIN RW0_rdata[78]
    DIRECTION OUTPUT ;
    USE SIGNAL ;
    SHAPE ABUTMENT ;
    PORT
      LAYER M4 ;
      RECT 0.000 18.288 0.084 18.312 ;
    END
  END RW0_rdata[78]
  PIN RW0_rdata[79]
    DIRECTION OUTPUT ;
    USE SIGNAL ;
    SHAPE ABUTMENT ;
    PORT
      LAYER M4 ;
      RECT 0.000 18.384 0.084 18.408 ;
    END
  END RW0_rdata[79]
  PIN RW0_rdata[80]
    DIRECTION OUTPUT ;
    USE SIGNAL ;
    SHAPE ABUTMENT ;
    PORT
      LAYER M4 ;
      RECT 0.000 18.480 0.084 18.504 ;
    END
  END RW0_rdata[80]
  PIN RW0_rdata[81]
    DIRECTION OUTPUT ;
    USE SIGNAL ;
    SHAPE ABUTMENT ;
    PORT
      LAYER M4 ;
      RECT 0.000 18.576 0.084 18.600 ;
    END
  END RW0_rdata[81]
  PIN RW0_rdata[82]
    DIRECTION OUTPUT ;
    USE SIGNAL ;
    SHAPE ABUTMENT ;
    PORT
      LAYER M4 ;
      RECT 0.000 18.672 0.084 18.696 ;
    END
  END RW0_rdata[82]
  PIN RW0_rdata[83]
    DIRECTION OUTPUT ;
    USE SIGNAL ;
    SHAPE ABUTMENT ;
    PORT
      LAYER M4 ;
      RECT 0.000 18.768 0.084 18.792 ;
    END
  END RW0_rdata[83]
  PIN RW0_rdata[84]
    DIRECTION OUTPUT ;
    USE SIGNAL ;
    SHAPE ABUTMENT ;
    PORT
      LAYER M4 ;
      RECT 0.000 18.864 0.084 18.888 ;
    END
  END RW0_rdata[84]
  PIN RW0_rdata[85]
    DIRECTION OUTPUT ;
    USE SIGNAL ;
    SHAPE ABUTMENT ;
    PORT
      LAYER M4 ;
      RECT 0.000 18.960 0.084 18.984 ;
    END
  END RW0_rdata[85]
  PIN RW0_rdata[86]
    DIRECTION OUTPUT ;
    USE SIGNAL ;
    SHAPE ABUTMENT ;
    PORT
      LAYER M4 ;
      RECT 0.000 19.056 0.084 19.080 ;
    END
  END RW0_rdata[86]
  PIN RW0_rdata[87]
    DIRECTION OUTPUT ;
    USE SIGNAL ;
    SHAPE ABUTMENT ;
    PORT
      LAYER M4 ;
      RECT 0.000 19.152 0.084 19.176 ;
    END
  END RW0_rdata[87]
  PIN RW0_rdata[88]
    DIRECTION OUTPUT ;
    USE SIGNAL ;
    SHAPE ABUTMENT ;
    PORT
      LAYER M4 ;
      RECT 0.000 19.248 0.084 19.272 ;
    END
  END RW0_rdata[88]
  PIN RW0_rdata[89]
    DIRECTION OUTPUT ;
    USE SIGNAL ;
    SHAPE ABUTMENT ;
    PORT
      LAYER M4 ;
      RECT 0.000 19.344 0.084 19.368 ;
    END
  END RW0_rdata[89]
  PIN RW0_rdata[90]
    DIRECTION OUTPUT ;
    USE SIGNAL ;
    SHAPE ABUTMENT ;
    PORT
      LAYER M4 ;
      RECT 0.000 19.440 0.084 19.464 ;
    END
  END RW0_rdata[90]
  PIN RW0_rdata[91]
    DIRECTION OUTPUT ;
    USE SIGNAL ;
    SHAPE ABUTMENT ;
    PORT
      LAYER M4 ;
      RECT 0.000 19.536 0.084 19.560 ;
    END
  END RW0_rdata[91]
  PIN RW0_rdata[92]
    DIRECTION OUTPUT ;
    USE SIGNAL ;
    SHAPE ABUTMENT ;
    PORT
      LAYER M4 ;
      RECT 0.000 19.632 0.084 19.656 ;
    END
  END RW0_rdata[92]
  PIN RW0_rdata[93]
    DIRECTION OUTPUT ;
    USE SIGNAL ;
    SHAPE ABUTMENT ;
    PORT
      LAYER M4 ;
      RECT 0.000 19.728 0.084 19.752 ;
    END
  END RW0_rdata[93]
  PIN RW0_rdata[94]
    DIRECTION OUTPUT ;
    USE SIGNAL ;
    SHAPE ABUTMENT ;
    PORT
      LAYER M4 ;
      RECT 0.000 19.824 0.084 19.848 ;
    END
  END RW0_rdata[94]
  PIN RW0_rdata[95]
    DIRECTION OUTPUT ;
    USE SIGNAL ;
    SHAPE ABUTMENT ;
    PORT
      LAYER M4 ;
      RECT 0.000 19.920 0.084 19.944 ;
    END
  END RW0_rdata[95]
  PIN RW0_rdata[96]
    DIRECTION OUTPUT ;
    USE SIGNAL ;
    SHAPE ABUTMENT ;
    PORT
      LAYER M4 ;
      RECT 0.000 20.016 0.084 20.040 ;
    END
  END RW0_rdata[96]
  PIN RW0_rdata[97]
    DIRECTION OUTPUT ;
    USE SIGNAL ;
    SHAPE ABUTMENT ;
    PORT
      LAYER M4 ;
      RECT 0.000 20.112 0.084 20.136 ;
    END
  END RW0_rdata[97]
  PIN RW0_rdata[98]
    DIRECTION OUTPUT ;
    USE SIGNAL ;
    SHAPE ABUTMENT ;
    PORT
      LAYER M4 ;
      RECT 0.000 20.208 0.084 20.232 ;
    END
  END RW0_rdata[98]
  PIN RW0_rdata[99]
    DIRECTION OUTPUT ;
    USE SIGNAL ;
    SHAPE ABUTMENT ;
    PORT
      LAYER M4 ;
      RECT 0.000 20.304 0.084 20.328 ;
    END
  END RW0_rdata[99]
  PIN RW0_rdata[100]
    DIRECTION OUTPUT ;
    USE SIGNAL ;
    SHAPE ABUTMENT ;
    PORT
      LAYER M4 ;
      RECT 0.000 20.400 0.084 20.424 ;
    END
  END RW0_rdata[100]
  PIN RW0_rdata[101]
    DIRECTION OUTPUT ;
    USE SIGNAL ;
    SHAPE ABUTMENT ;
    PORT
      LAYER M4 ;
      RECT 0.000 20.496 0.084 20.520 ;
    END
  END RW0_rdata[101]
  PIN RW0_rdata[102]
    DIRECTION OUTPUT ;
    USE SIGNAL ;
    SHAPE ABUTMENT ;
    PORT
      LAYER M4 ;
      RECT 0.000 20.592 0.084 20.616 ;
    END
  END RW0_rdata[102]
  PIN RW0_rdata[103]
    DIRECTION OUTPUT ;
    USE SIGNAL ;
    SHAPE ABUTMENT ;
    PORT
      LAYER M4 ;
      RECT 0.000 20.688 0.084 20.712 ;
    END
  END RW0_rdata[103]
  PIN RW0_addr[0]
    DIRECTION INPUT ;
    USE SIGNAL ;
    SHAPE ABUTMENT ;
    PORT
      LAYER M4 ;
      RECT 0.000 20.784 0.084 20.808 ;
    END
  END RW0_addr[0]
  PIN RW0_addr[1]
    DIRECTION INPUT ;
    USE SIGNAL ;
    SHAPE ABUTMENT ;
    PORT
      LAYER M4 ;
      RECT 0.000 20.880 0.084 20.904 ;
    END
  END RW0_addr[1]
  PIN RW0_addr[2]
    DIRECTION INPUT ;
    USE SIGNAL ;
    SHAPE ABUTMENT ;
    PORT
      LAYER M4 ;
      RECT 0.000 20.976 0.084 21.000 ;
    END
  END RW0_addr[2]
  PIN RW0_addr[3]
    DIRECTION INPUT ;
    USE SIGNAL ;
    SHAPE ABUTMENT ;
    PORT
      LAYER M4 ;
      RECT 0.000 21.072 0.084 21.096 ;
    END
  END RW0_addr[3]
  PIN RW0_addr[4]
    DIRECTION INPUT ;
    USE SIGNAL ;
    SHAPE ABUTMENT ;
    PORT
      LAYER M4 ;
      RECT 0.000 21.168 0.084 21.192 ;
    END
  END RW0_addr[4]
  PIN RW0_addr[5]
    DIRECTION INPUT ;
    USE SIGNAL ;
    SHAPE ABUTMENT ;
    PORT
      LAYER M4 ;
      RECT 0.000 21.264 0.084 21.288 ;
    END
  END RW0_addr[5]
  PIN RW0_addr[6]
    DIRECTION INPUT ;
    USE SIGNAL ;
    SHAPE ABUTMENT ;
    PORT
      LAYER M4 ;
      RECT 0.000 21.360 0.084 21.384 ;
    END
  END RW0_addr[6]
  PIN RW0_addr[7]
    DIRECTION INPUT ;
    USE SIGNAL ;
    SHAPE ABUTMENT ;
    PORT
      LAYER M4 ;
      RECT 0.000 21.456 0.084 21.480 ;
    END
  END RW0_addr[7]
  PIN RW0_wmode
    DIRECTION INPUT ;
    USE SIGNAL ;
    SHAPE ABUTMENT ;
    PORT
      LAYER M4 ;
      RECT 0.000 21.552 0.084 21.576 ;
    END
  END RW0_wmode
  PIN RW0_en
    DIRECTION INPUT ;
    USE SIGNAL ;
    SHAPE ABUTMENT ;
    PORT
      LAYER M4 ;
      RECT 0.000 21.648 0.084 21.672 ;
    END
  END RW0_en
  PIN RW0_clk
    DIRECTION INPUT ;
    USE SIGNAL ;
    SHAPE ABUTMENT ;
    PORT
      LAYER M4 ;
      RECT 0.000 21.744 0.084 21.768 ;
    END
  END RW0_clk
  PIN VSS
    DIRECTION INOUT ;
    USE GROUND ;
    PORT
      LAYER M4 ;
      RECT 0.156 0.000 28.014 0.120 ;
      RECT 0.156 0.756 28.014 0.876 ;
      RECT 0.156 1.524 28.014 1.644 ;
      RECT 0.156 2.292 28.014 2.412 ;
      RECT 0.156 3.060 28.014 3.180 ;
      RECT 0.156 3.828 28.014 3.948 ;
      RECT 0.156 4.596 28.014 4.716 ;
      RECT 0.156 5.364 28.014 5.484 ;
      RECT 0.156 6.132 28.014 6.252 ;
      RECT 0.156 6.900 28.014 7.020 ;
      RECT 0.156 7.668 28.014 7.788 ;
      RECT 0.156 8.436 28.014 8.556 ;
      RECT 0.156 9.204 28.014 9.324 ;
      RECT 0.156 9.972 28.014 10.092 ;
      RECT 0.156 10.740 28.014 10.860 ;
      RECT 0.156 11.508 28.014 11.628 ;
      RECT 0.156 12.276 28.014 12.396 ;
      RECT 0.156 13.044 28.014 13.164 ;
      RECT 0.156 13.812 28.014 13.932 ;
      RECT 0.156 14.580 28.014 14.700 ;
      RECT 0.156 15.348 28.014 15.468 ;
      RECT 0.156 16.116 28.014 16.236 ;
      RECT 0.156 16.884 28.014 17.004 ;
      RECT 0.156 17.652 28.014 17.772 ;
      RECT 0.156 18.420 28.014 18.540 ;
      RECT 0.156 19.188 28.014 19.308 ;
      RECT 0.156 19.956 28.014 20.076 ;
      RECT 0.156 20.724 28.014 20.844 ;
      RECT 0.156 21.492 28.014 21.612 ;
      RECT 0.156 22.260 28.014 22.380 ;
      RECT 0.156 23.028 28.014 23.148 ;
      RECT 0.156 23.796 28.014 23.916 ;
      RECT 0.156 24.564 28.014 24.684 ;
      RECT 0.156 25.332 28.014 25.452 ;
    END
  END VSS
  PIN VDD
    DIRECTION INOUT ;
    USE POWER ;
    PORT
      LAYER M4 ;
      RECT 0.156 0.372 28.014 0.492 ;
      RECT 0.156 1.140 28.014 1.260 ;
      RECT 0.156 1.908 28.014 2.028 ;
      RECT 0.156 2.676 28.014 2.796 ;
      RECT 0.156 3.444 28.014 3.564 ;
      RECT 0.156 4.212 28.014 4.332 ;
      RECT 0.156 4.980 28.014 5.100 ;
      RECT 0.156 5.748 28.014 5.868 ;
      RECT 0.156 6.516 28.014 6.636 ;
      RECT 0.156 7.284 28.014 7.404 ;
      RECT 0.156 8.052 28.014 8.172 ;
      RECT 0.156 8.820 28.014 8.940 ;
      RECT 0.156 9.588 28.014 9.708 ;
      RECT 0.156 10.356 28.014 10.476 ;
      RECT 0.156 11.124 28.014 11.244 ;
      RECT 0.156 11.892 28.014 12.012 ;
      RECT 0.156 12.660 28.014 12.780 ;
      RECT 0.156 13.428 28.014 13.548 ;
      RECT 0.156 14.196 28.014 14.316 ;
      RECT 0.156 14.964 28.014 15.084 ;
      RECT 0.156 15.732 28.014 15.852 ;
      RECT 0.156 16.500 28.014 16.620 ;
      RECT 0.156 17.268 28.014 17.388 ;
      RECT 0.156 18.036 28.014 18.156 ;
      RECT 0.156 18.804 28.014 18.924 ;
      RECT 0.156 19.572 28.014 19.692 ;
      RECT 0.156 20.340 28.014 20.460 ;
      RECT 0.156 21.108 28.014 21.228 ;
      RECT 0.156 21.876 28.014 21.996 ;
      RECT 0.156 22.644 28.014 22.764 ;
      RECT 0.156 23.412 28.014 23.532 ;
      RECT 0.156 24.180 28.014 24.300 ;
      RECT 0.156 24.948 28.014 25.068 ;
      RECT 0.156 25.716 28.014 25.836 ;
    END
  END VDD
  OBS
    LAYER M1 ;
    RECT 0 0 28.17 26.071 ;
    LAYER M2 ;
    RECT 0 0 28.17 26.071 ;
    LAYER M3 ;
    RECT 0 0 28.17 26.071 ;
  END
END array_256x104

END LIBRARY
